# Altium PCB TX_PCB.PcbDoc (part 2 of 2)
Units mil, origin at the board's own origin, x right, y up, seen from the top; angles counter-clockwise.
Board outline 1955 x 2115 mil, 2 copper layers (Top Layer, Bottom Layer); 123 components, 95 nets, 485 pads, 266 vias.
Unrouted connection lines stored in the file: 109.

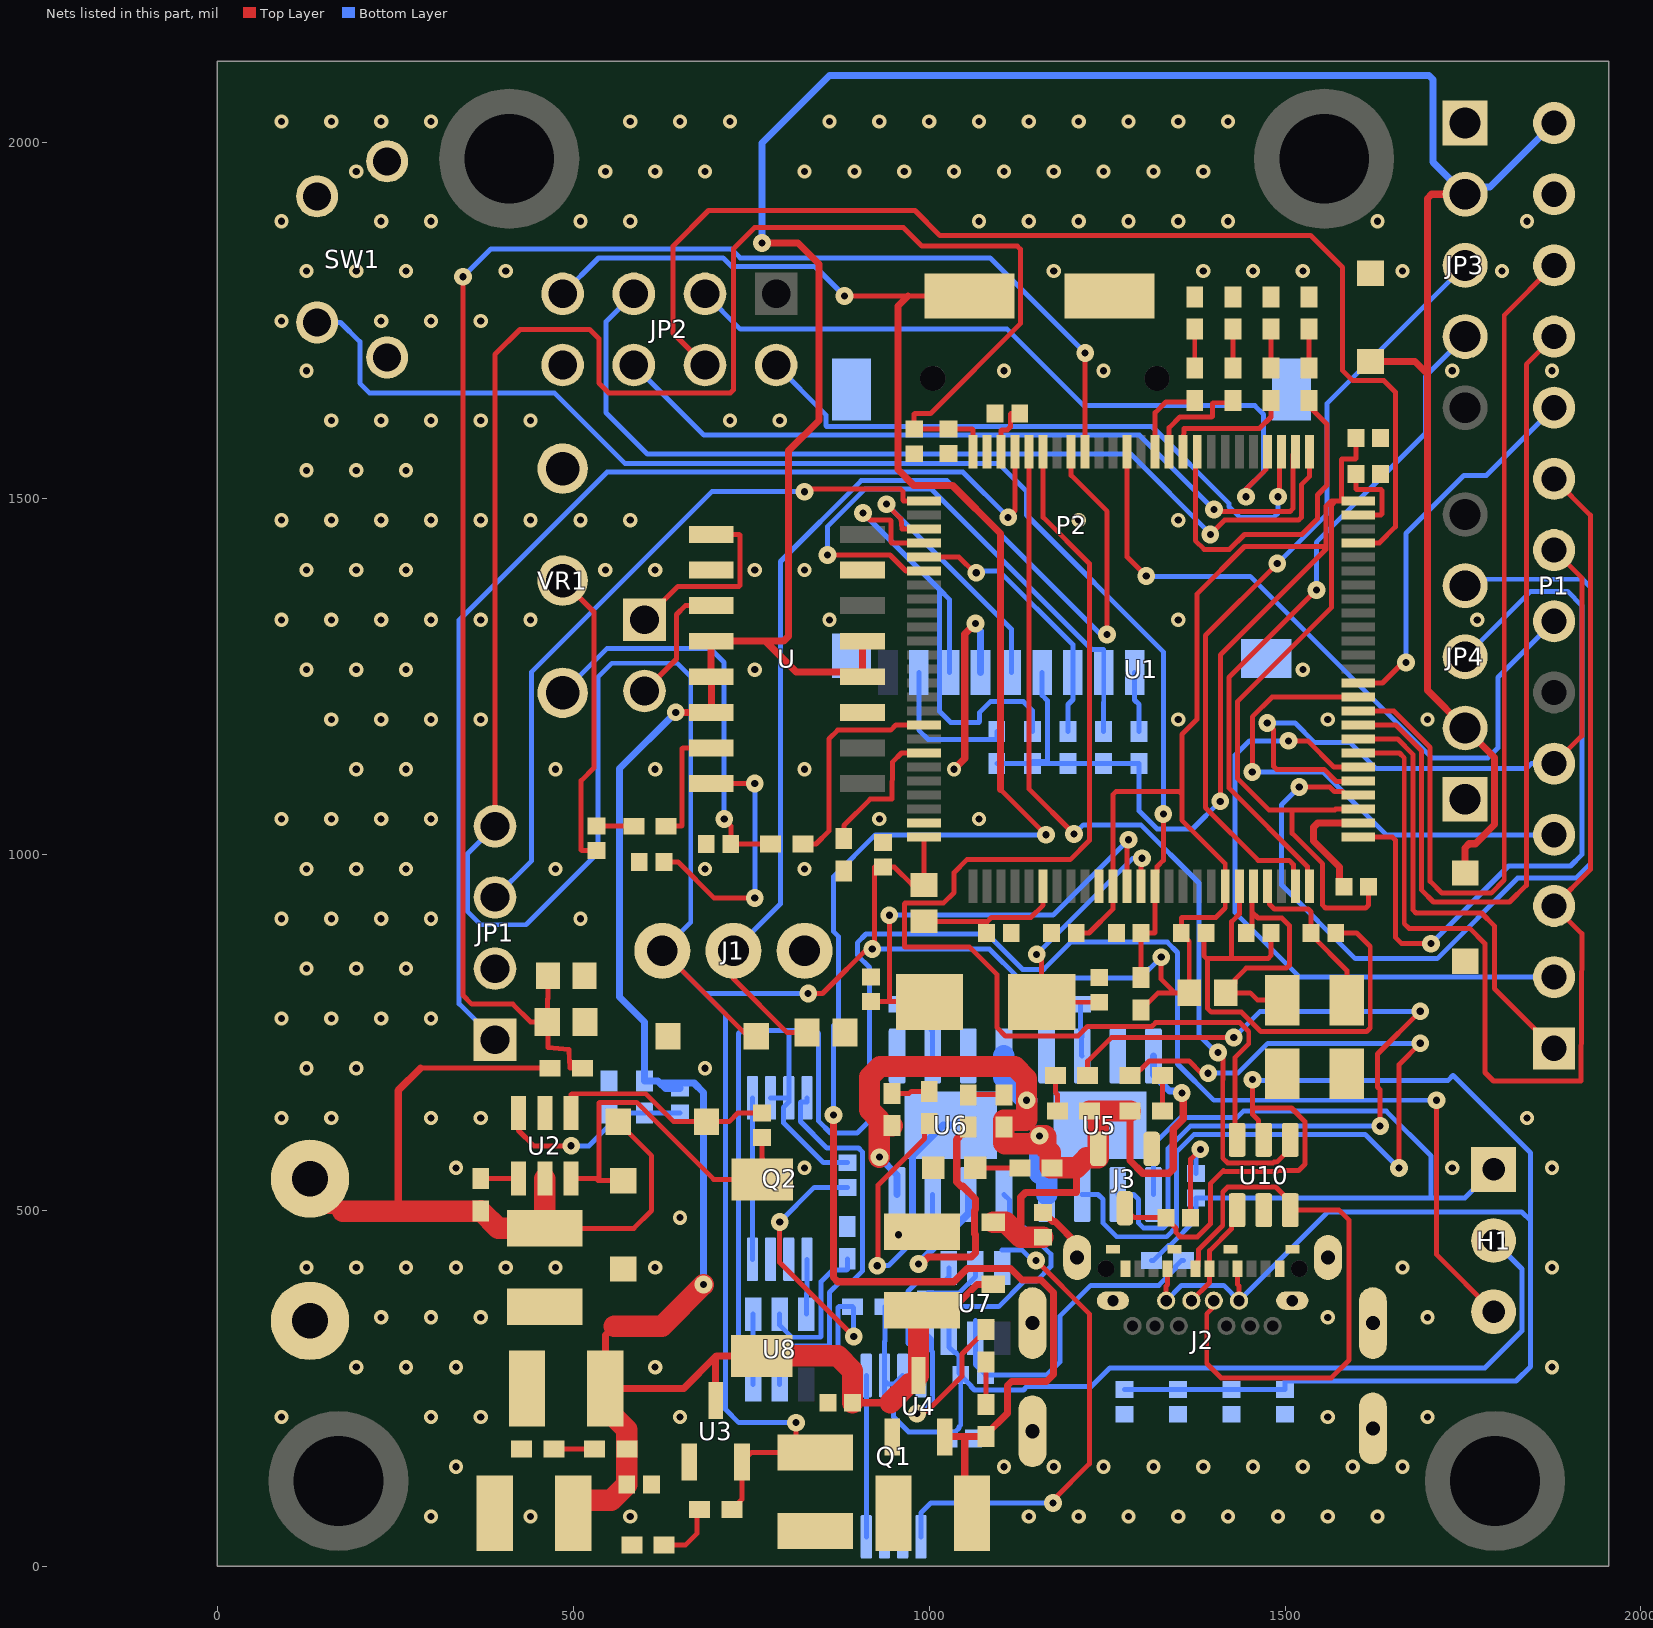
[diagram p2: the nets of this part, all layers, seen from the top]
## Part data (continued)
U: "Amplifier IC 2-Channel _Stereo_ Class D 16-SOP", Package="SOP-16 Diodes Inc."
U1: "ARMÂ® CortexÂ®-M4 STM32F4 Microcontroller IC 32-Bit Single-Core 168MHz 512KB (512K x 8) FLASH 100-LQFP (14x14)", Package="LQFP-100 STMicroelectronics"
U2: "Buck Switching Regulator IC Positive Adjustable 0.8V 1 Output 1A SOT-23-6 Thin, TSOT-23-6", Package="SOT-23 Texas Instruments"
U3 U4: "Linear Voltage Regulator IC 1 Output 250mA SOT-23-3", Package="SOT-23-3 Microchip"
U5 U6: "Complete single cell Li-Ion battery with a constant current / constant voltage linear charger", Package=Package
U7 U8: "One Cell Lithium-ion/Polymer Battery Protection IC", Package="SOT-23-6 Fortune Semiconductor"
U10: "17V Clamp 5A (8/20Âµs) Ipp Tvs Diode Surface Mount SOT-23-6", Package="SOT-23-6 STMicroelectronics"
Y1: library part NX5032GA-8.000M-STD-CSU-1, "CRYSTAL 8.0000MHZ 8PF SMD", ESR (Equivalent Series Resistance)="300 Ohms", Frequency Stability=±150ppm, Frequency Tolerance=±50ppm, Load Capacitance=8pF, Manufacturer="NDK America, Inc.", Operating Mode=Fundamental, Operating Temperature="-40°C ~ 150°C", Package / Case="2-SMD, No Lead", Ratings=AEC-Q200, Supplier Part Number 1=644-1132-1-ND

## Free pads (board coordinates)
  round 196.85 hole 125.98: 8(170,120) 8(410,1977.8) 8(1555,1977.8) 8(1795,120)

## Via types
v1: diameter 20, hole 10, Top Layer to Bottom Layer, 198 vias
v2: diameter 25, hole 10, Top Layer to Bottom Layer, 66 vias
v3: diameter 70.87, hole 59.06, Top Layer to Bottom Layer, 2 vias

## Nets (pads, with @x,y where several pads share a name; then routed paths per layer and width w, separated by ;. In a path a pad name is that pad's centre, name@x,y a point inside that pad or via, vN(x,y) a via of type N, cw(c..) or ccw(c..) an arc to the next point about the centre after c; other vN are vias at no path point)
+5: C19.2 C22.2 C23.2 C26.2 C31.2 C32.2 D6.2 D8.2 D9.2 JP3.2 JP4.2 L1.2 P1.14 R19.2 R21.2 U3.3 U4.3 U.4 U.5 U.6 U.12 U.13 | length 5966.3
  Top Layer w10: C22.2@545.12,249.92 C22.2@545.12,250 ; 557.62,337.5 545.12,325 C22.2@545.12,250 ; v2(644,1200) U.6@693.7,1200 694,1200 694,1250 U.5@693.7,1250 U.4@693.7,1300 770,1300 ; U3.3@700,232.92 700,294.9 ; L1.2@764.51,295.91 701,295.91 700,294.9 ; v2(765.05,1859.5) 815.5,1859.5 845,1830 845,1610 802.5,1567.5 802.5,1307 795.5,1300 770,1300 ; C32.2@892.32,229.92 945.35,229.92 ; U.13@906.3,1300 U.12@906.3,1250 899.49,1256.81 813.19,1256.81 770,1300 ; U4.3@980,256.92 985,261.92 U4.3@985,267.92 ; C31.2@990,349.8 1020.68,349.8 1067,396.12 D6.2@1090,396.12 ; D8.2@1620,1692.99 1682.5,1692.99 1700,1675.49 ; D9.2@1753,974.3 1753,1009.54 1758.86,1015.4 1767.54,1015.4 1794.5,1042.36 1794.5,1136.5 JP4.2@1753,1178 1700,1231 1700,1675.49 ; JP3.2@1753,1928 1705.86,1928 1700,1922.14 1700,1725 1700,1675.49 ; C22.2@545.12,250 655.09,250 700,294.9
  Top Layer w30: C23.2@500.12,74.92 500.12,82.35 510.71,92.94 553.14,92.94 C26.2@575.12,114.92 R21.2@575.12,164.92 575.12,192.36 545.12,222.36 C22.2@545.12,249.92 ; 557.62,337.5 624.5,337.5 v2(683,396) ; L1.2@764.51,295.91 871.42,295.91 892.32,275 C32.2@892.32,229.92 ; 945.35,229.92 972.35,256.92 U4.3@980,256.92 ; U4.3@985,267.92 985,349.8 C31.2@990,349.8
  Bottom Layer w10: v2(644,1200) 565,1121 565,800 600,765 R19.2@600,682.2 619,682.2 622.2,679 ; C19.2@650,671.88 629.31,671.88 622.2,679 ; v2(683,396) 683,666 670,679 650,679 622.2,679 ; v2(765.05,1859.5) 765.05,2000.05 860,2095 1702.14,2095 1708,2089.14 1708,1973 JP3.2@1753,1928 1763.14,1938.14 1788.14,1938.14 P1.14@1878,2028
+5_USB: C43.1 D6.1 D16.1 D17.1 D18.1 D19.1 J3.2 R36.2 U5.4 U5.8 U6.4 U6.8 | length 1613.2
  Top Layer w10: 1128.62,462.6 1128.62,518.62 1135.64,525.64 1207,525.64 1207,559.92 ; 1257.6,642.3 1259.98,639.92 ; D17.1@1282.36,639.92 1282.36,570.13 1300.05,552.44 1337.14,552.44 1343,558.3 1343,614.57 1357,628.57 1357,663 v2(1355,665)
  Top Layer w30: v2(930,575) 930,627.7 916.14,641.56 916.14,687.66 930.81,702.32 1120.1,702.32 1136.81,685.61 1136.81,655.19 v2(1137,655) 1137,628 1136,627 1105,627 D19.1@1105,617.28 1105,595 1106,594 v2@1157.5,594 ; 930,619.33 D18.1@947.95,619.33 ; D6.1@1090,483.72 1107.5,483.72 1128.62,462.6 C43.1@1160,462.6 ; v2(1155,605) 1163,605 1164,604 1164,587.5 1170,581.5 1170,559.92 R36.2@1172.64,559.92 1207,559.92 1221.08,574 1237.6,574 J3.2@1237.6,586.65 D16.1@1237.6,639.92 ; D16.1@1225.28,639.92 D16.1@1237.6,639.92 ; D17.1@1282.36,639.92 1259.98,639.92 D16.1@1237.6,639.92
  Bottom Layer w10: v2(930,575) 955,550 U6.8@955,522.48 ; U5.4@1315,717.36 1315,690.39 1337.52,667.87 1352.13,667.87 v2(1355,665)
  Bottom Layer w30: U6.4@1105,717.36 1105,687 v2(1137,655) ; v2(1155,605) 1155,552 1165,552 U5.8@1165,522.48
+5_USB_A: C34.1 C35.1 C36.1 C37.1 C42.2 J2.A4 J2.A9 J2.B4 J2.B9 J3.3 U10.5 | length 2590.6
  Top Layer w7: J3.3@1275,503.19 1288.27,489.92 C42.2@1332.68,489.92 1332.68,489.13 1347.01,474.8 1347.01,468.99 1353.1,462.9 1376.73,462.9 1394.97,481.14 1394.97,537.76 1413.2,556 1414.19,555.01 1488.4,555.01 1489.39,556 1518.9,556 1528,565.1 1528,625 1509,644 1461.92,644 1461.7,644.21 1454.29,644.21 ; J2.B9@1332.99,373.39 1332.99,394 1334.96,395.97 J2.A4@1334.96,418.27 ; J2.A9@1433.39,418.27 1433.39,395.97 1435.35,394 J2.B4@1435.35,373.39 ; v2(1454.29,683.89) 1454.29,644.21 ; U10.5@1470,599.33 1462.82,606.51 1462.82,626.73 1454.29,635.27 1454.29,644.21
  Bottom Layer w7: C35.1@1274.61,248.43 C34.1@1349.74,248.43 C36.1@1424.87,248.43 C37.1@1500,248.43 1500,260.5 1824.5,260.5 1845,281 1845,485.5 ; J2.B9@1332.99,373.39 1354.6,395 1413.74,395 J2.B4@1435.35,373.39 1559.97,498 1832.5,498 1845,485.5 ; v2(1454.29,683.89) 1455.18,683 1729.15,683 1736.04,689.89 1845,580.94 1845,485.5
+8.4: C21.2 D1.1 KF1.1 R7.2 R20.2 U2.5 | length 1156.7
  Top Layer w7: KF1.1@130,544.92 130,499 164.92,499 175.92,499 ; 285.08,700 R7.2@467.36,700 ; C21.2@460,475.04 585.04,475.04 610,500 610,576.93 562.99,623.94 D1.1@562.99,624.92
  Top Layer w10: 254,499 254,510 254,668.92 285.08,700
  Top Layer w30: 175.92,499 254,499 369.35,499 R20.2@370,499.65 ; R20.2@370.32,499.32 394.61,475.04 C21.2@460,475.04 U2.5@460,544.92
ADC_Pin: C29.2 R7.1 R15.2 U1.67 | length 2408
  Top Layer w7: v2(345,1812) 345,802.5 357.5,790 415,790 440,765 C29.2@463.43,765 ; R15.2@464.41,830 464.41,797.98 463.43,797 C29.2@463.43,765 ; R7.1@512.64,700 495,700 494,726 464.43,729 C29.2@463.43,765 ; U1.67@1219.15,1566 v2(1219.15,1704.85)
  Bottom Layer w7: v2(345,1812) 384,1851 722,1851 734.5,1838.5 1085.5,1838.5 v2(1219.15,1704.85)
ADC_VR_ESC: C24.2 J1.2 U1.68 | length 1621.5
  Top Layer w7: J1.2@725,865 725,825.5 800.5,750 C24.2@828.42,750 ; U1.68@1199.47,1566 1199.47,1533 1250,1482.47 v2(1250,1309.48)
  Bottom Layer w7: J1.2@725,865 791,931 791,1411.97 904.53,1525.5 1025.02,1525.5 1241.04,1309.48 v2(1250,1309.48)
Audio_PWM: R8.2 U1.92 | length 315.2
  Top Layer w7: R8.2@822.64,1015 841,1015 859,1033 859,1162.5 871.5,1175 946,1175 953.14,1182.14 U1.92@992.77,1182.14
B+: C38.1 H1.1 R27.2 U5.5 | length 1116.1
  Bottom Layer w7: R27.2@1312.36,430 1315.31,430 1336.52,451.2 1338.54,451.2 1375,487.66 C38.1@1375,517.6 1705,517.6 ; U5.5@1315,522.48 1315,592.64 1353.36,631 1432.64,631 1441.29,639.65 1642.35,639.65 1705,577 1705,517.6 ; H1.1@1793,557.92 1752.68,517.6 1705,517.6
B-: C41.2 H1.3 Q2.2 Q2.3 U8.6 | length 2725.1
  Top Layer w7: v2(1713,655) 1713,437.92 H1.3@1793,357.92
  Bottom Layer w7: U8.6@752.6,255.51 752.6,294.4 732,315 732,748.73 736.1,752.84 799.96,752.84 ; Q2.2@777.2,658.31 Q2.3@802.8,658.31 ; C41.2@885,567.25 851.48,567.25 795.39,623.34 795.39,645.13 802.8,652.54 Q2.3@802.8,658.31 ; v2(1713,655) 1400,655 1349,706 1349,862.7 1334.7,877 1199,877 1161,839 1131,839 1081.5,888.5 911.3,888.5 899,876.2 899,858.8 916.28,841.52 916.28,626.49 898.79,609 861.3,609 844.76,625.54 844.76,748.73 840.66,752.84 802.8,752.84 799.96,752.84 ; 799.96,752.84 802.8,750 Q2.3@802.8,658.31
B_COM: C39.2 C40.1 H1.2 Q1.2 Q1.3 R31.2 U6.5 U7.6 | length 1771.9
  Bottom Layer w7: 937.2,237.5 Q1.2@937.2,260.75 ; R31.2@937.64,364.92 937.64,316.43 937.2,316 Q1.2@937.2,260.75 ; Q1.3@962.8,268.31 950.87,256.38 ; C40.1@1027.68,180 C40.1@1027.68,180.79 ; U6.5@1105,522.48 1112.98,514.5 1112.98,480.75 1118.53,475.2 1134.5,475.2 1171,438.7 1171,421.3 1150.48,400.79 1133.33,400.79 1097.54,365 1037.61,365 1027.6,354.99 1027.6,308.39 1035.71,300.27 1037.44,300.27 1041.54,296.17 1041.54,271.81 C39.2@1044.36,269 ; H1.2@1793,457.92 1833,417.93 1833,331 1781,279 1254,279 1228,253 1137.51,253 1132.41,247.9 1063.67,247.9 1058.69,252.88 1058.69,253.88 1044.36,268.21 C39.2@1044.36,269 ; Q1.2@937.2,260.75 941.58,256.38 950.87,256.38 ; 950.87,256.38 950,255.51 950,210 970.9,189.1 1019.37,189.1 C40.1@1027.68,180.79 ; C40.1@1027.68,180.79 1035.99,189.1 1036.78,189.1 1042.01,194.33 1042.01,196.12 1044.36,198.46 C39.2@1044.36,269
BOOT0: R6.2 U1.94 | length 203
  Top Layer w7: R6.2@880,1022.64 880,1041 917,1078 947.65,1078 948.65,1130.42 961,1142.77 U1.94@992.77,1142.77
CHRG_LED: R28.1 U5.7 | length 1257.6
  Top Layer w7: R28.1@1282.36,689.92 1289.04,689.92 1304.37,705.25 1309.35,710.23 1365.23,710.23 1382.47,693 v2(1392,693) ; v2(1660,560) 1660,705 v2(1690,735)
  Bottom Layer w7: U5.7@1215,522.48 1237.31,522.48 1244.35,515.44 1244.35,482.25 1263.4,463.2 1333.57,463.2 1347.31,476.94 1347.31,582.01 1372.3,607 1612.46,607 1659.46,560 v2(1660,560) ; v2(1392,693) 1433.7,693 1475.7,735 v2(1690,735)
CHRG_LED_1: R32.1 U6.7 | length 371.5
  Top Layer w7: v2(927.1,422.5) 928.35,423.75 928.35,535.85 993.68,601.18 993.68,615.96 R32.1@1000,622.28
  Bottom Layer w7: v2(927.1,422.5) 942.96,422.5 1005,484.54 U6.7@1005,522.48
CLK_SD: P2.5 U1.78 | length 383.7
  Top Layer w7: v2(940,1492.5) 960.27,1472.23 961.54,1457.73 U1.78@992.77,1457.73
  Bottom Layer w7: v2(940,1492.5) 1115.35,1317.15 P2.5@1115.35,1255.88
CS_SD: P2.2 R18.1 U1.81 | length 803.2
  Top Layer w7: v2(857,1421) 945,1421 967.32,1398.68 U1.81@992.77,1398.68
  Bottom Layer w7: v2(857,1421) 857,1461 909.5,1513.5 1003.15,1513.5 1228.14,1288.51 1244.77,1288.51 1245.28,1288 P2.2@1245.28,1255.88 1245.28,1214.28 1245,1214 R18.1@1245,1173.36
DISPL_CS: P1.12 U1.35 | length 1321.3
  Top Layer w7: U1.35@1603.01,1201.83 1652.76,1201.83 1704,1150.58 1704,962.57 1720.57,946 1789.5,946 1808,964.5 1808,1758 P1.12@1878,1828
DISPL_DC: P1.10 U1.37 | length 541.6
  Top Layer w7: U1.37@1603.01,1241.2 1637,1241.2 1665.8,1270 v2(1670,1270)
  Bottom Layer w7: v2(1670,1270) 1670,1451.56 1751.44,1533 1783,1533 P1.10@1878,1628
DISPL_LED: P1.7 U1.64 | length 1002
  Top Layer w7: U1.64@1278.21,1566 1278.21,1418.29 v2(1305,1391.5)
  Bottom Layer w7: v2(1305,1391.5) 1305.5,1391 1451,1391 1706,1136 1785,1136 1799,1150 1799,1249 P1.7@1878,1328
DISPL_MOSI: P1.3 P1.9 U1.32 | length 1650.8
  Top Layer w7: U1.32@1603.01,1142.77 1660.9,1142.77 1667.5,1136.17 1667.5,903.11 1674.1,896.51 1759.49,896.51 1781,875 1781,694 1793,682 1916,682 1917,889 P1.3@1878,928 1929,979 1929,1477 P1.9@1878,1528
DISPL_RST: P1.11 U1.34 | length 1250.4
  Top Layer w7: U1.34@1603.01,1182.14 1655.47,1182.14 1692,1145.61 1692,950.1 1708.64,933.46 1815.46,933.46 1839,957 1839,1689 P1.11@1878,1728
DISPL_SCK: P1.5 P1.8 U1.30 | length 957.5
  Top Layer w7: v2(1475,1185) 1484,1176 1484,1124.1 1488.1,1120 1555,1120 1572.16,1102.84 1602.45,1102.84 U1.30@1603.01,1103.4 ; P1.5@1878,1128 1917,1167 1917,1389 P1.8@1878,1428
  Bottom Layer w7: v2(1475,1185) 1514.2,1185 1541.8,1157.4 1591.6,1157.4 1628.17,1120.83 1838.83,1120.83 1846,1128 P1.5@1878,1128
GND: C1.1 C2.1 C3.1 C4.1 C5.1 C6.1 C7.2 C8.1 C9.1 C10.1 C11.1 C12.1 C13.1 C14.1 C15.1 C17.1 C18.1 C21.1 C22.1 C23.1 C24.1 C25.2 C26.1 C27.2 C28.1 C29.1 C30.2 C31.1 C32.1 C33.1 C34.2 C35.2 C36.2 C37.2 C38.2 C40.2 C42.1 C43.2 D2.1 D3.2 D4.1 D5.2 D8.1 D9.1 D10.2 D11.2 D12.2 D13.2 D14.2 D15.2 J1.1 J2.A1 J2.A12 J2.B1 J2.B12 J2.S J3.1 JP1.2 JP2.5 JP3.1 JP4.1 KF1.2 P1.13 P2.6 P2.G1 P2.G2 P2.G3 P2.G4 Q1.6 Q1.7 Q2.6 Q2.7 R6.1 R10.1 R15.1 R22.1 R25.1 R26.2 R30.2 SW1.1 SW1.G1 SW1.G2 U1.10 U1.20 U1.27 U1.74 U1.99 U2.2 U3.1 U4.1 U5.1 U5.3 U5.9 U6.1 U6.3 U6.9 U10.2 U.2 U.11 U.15 VR1.2 | length 1920.6
  Top Layer w7: v2(983,215) 986.44,218.44 997.44,218.44 1046,267 1046,298.56 1068.74,321.3 1071.69,321.3 1080,329.61 D15.2@1080,332.56 ; C42.1@1367.32,489.92 1367.32,572.32 v2(1381,586) ; C12.1@1388.92,890 1386,887.07 1386,858.1 1390.1,854 ; U1.20@1435.69,955.76 1435.69,916.64 1425,905.95 1425,854 ; C6.1@1480.12,890 1480.12,858.12 1476,854 1425,854 ; C7.2@1571.32,890 1600.68,890 1619.71,870.97 1619.71,756.62 1614.73,751.64 1466.03,751.64 1438.87,778.8 1396.34,778.8 1391.36,783.78 1391.36,852.74 1390.1,854 ; 1390.1,854 1425,854
  Top Layer w10: v1(1035,1120) 1050,1135 1050,1310 v2(1065,1325) ; C43.2@1160,497.25 1160.79,497.25 1173.62,484.41 1176.74,484.41 1207.99,453.16 J2.S@1207.99,434.02 ; C11.1@1582.68,955 1576.49,961.18 1576.49,982.6 1540,1019.09 1540,1038.49 1545.86,1044.35 U1.27@1603.01,1044.35
  Bottom Layer w7: v2(983,215) 984.53,215 1004.76,235.23 1004.76,301.38 1003.31,302.83 1003.31,319.05 R26.2@995,327.36 ; C38.2@1375,552.24 1375,580 v2(1381,586)
  Bottom Layer w10: v2(956.76,466) 961.52,466 976.81,481.29 976.81,577.42 1019.31,619.92 U6.9@1030,619.92 ; R26.2@994,326 995,327 R26.2@995,327.36 ; v2(1065,1325) 1065,1320.94 1072.05,1313.89 P2.6@1072.05,1255.88
  other v1: 300,70 440,70 580,70 1140,70 1210,70 1280,70 1350,70 1420,70 1490,70 1560,70 1630,70 335,140 1105,140 1175,140 1245,140 1315,140 1385,140 1455,140 1525,140 1595,140 1665,140 90,210 300,210 370,210 650,210 1560,210 1700,210 195,280 265,280 335,280 615,280 1875,280 230,350 300,350 370,350 1560,350 1700,350 125,420 195,420 265,420 335,420 405,420 475,420 615,420 1665,420 1875,420 650,490 335,560 825,560 1735,560 1875,560 90,630 160,630 300,630 370,630 1840,630 125,700 195,700 685,700 90,770 160,770 230,770 300,770 125,840 195,840 265,840 90,910 160,910 230,910 300,910 510,910 125,980 195,980 265,980 475,980 685,980 825,980 90,1050 160,1050 230,1050 300,1050 930,1050 1070,1050 195,1120 265,1120 475,1120 615,1120 825,1120 160,1190 230,1190 300,1190 370,1190 1350,1190 1560,1190 1700,1190 125,1260 195,1260 265,1260 755,1260 1525,1260 90,1330 160,1330 230,1330 300,1330 370,1330 440,1330 860,1330 1350,1330 1770,1330 125,1400 195,1400 265,1400 545,1400 615,1400 755,1400 825,1400 90,1470 160,1470 230,1470 300,1470 370,1470 440,1470 510,1470 580,1470 1210,1470 1350,1470 125,1540 195,1540 265,1540 160,1610 230,1610 300,1610 370,1610 440,1610 720,1610 790,1610 125,1680 1105,1680 1245,1680 1735,1680 1875,1680 90,1750 230,1750 300,1750 370,1750 125,1820 195,1820 265,1820 405,1820 1175,1820 1385,1820 1455,1820 1525,1820 1665,1820 1805,1820 90,1890 230,1890 300,1890 510,1890 580,1890 1070,1890 1140,1890 1210,1890 1280,1890 1350,1890 1420,1890 1630,1890 1840,1890 195,1960 545,1960 615,1960 685,1960 825,1960 895,1960 965,1960 1035,1960 1105,1960 1175,1960 1245,1960 1315,1960 1385,1960 90,2030 160,2030 230,2030 300,2030 580,2030 650,2030 720,2030 860,2030 930,2030 1000,2030 1070,2030 1140,2030 1210,2030 1280,2030 1350,2030 1420,2030
JOY1_X: JP3.3 U1.24 | length 1101.3
  Top Layer w7: v2(1489,1409) 1388,1308 1388,1066.3 1462.3,992 1505.88,992 1511.63,986.25 1511.63,958.56 U1.24@1514.43,955.76
  Bottom Layer w7: v2(1489,1409) 1559.23,1479.23 1559.23,1634.23 JP3.3@1753,1828
JOY1_Y: JP3.4 U1.25 | length 956.6
  Top Layer w7: U1.25@1534.11,955.76 1531.31,958.56 1531.31,983.53 1421,1093.85 1421,1249 v2(1544,1372)
  Bottom Layer w7: v2(1544,1372) 1544,1438.87 1697,1591.87 1697,1672 JP3.4@1753,1728
JOY2_X: JP4.3 U1.26 | length 1068.2
  Top Layer w7: U1.26@1603.01,1024.66 1650.9,1024.66 1655,1020.56 1655,883.87 1663.87,875 v2(1705,875)
  Bottom Layer w7: v2(1705,875) 1814,984 1901,984 1917,1000 1917,1350 1897,1370 1845,1370 JP4.3@1753,1278
JOY2_Y: JP4.4 U1.29 | length 1345.7
  Top Layer w7: v2(1520,1095) 1563.03,1095 1569.43,1088.6 1580.8,1088.6 1585.69,1083.72 U1.29@1603.01,1083.72
  Bottom Layer w7: v2(1520,1095) 1495,1070 1495,957.68 1598.68,854 1713.7,854 1826.7,967 1908.5,967 1929,987.5 1929,1376 1918,1387 1753,1387 JP4.4@1753,1378
LED1: R1.1 U1.59 | length 502.7
  Top Layer w7: U1.59@1376.63,1566 1374,1563.37 1374,1441.3 1386.3,1429 1422.03,1429 1443.03,1450 1523.64,1450 1545.5,1471.86 1545.5,1505.5 1559,1519 1559,1604.72 1533.72,1630 R1.1@1533.72,1638.36
LED2: R2.1 U1.60 | length 185.3
  Top Layer w7: U1.60@1356.95,1566 1357.95,1599 1464.19,1599 1480.19,1615 R2.1@1480.19,1638.36
LED3: R3.1 U1.61 | length 151.8
  Top Layer w7: U1.61@1337.26,1566 1337.26,1600 1352.26,1615 1397,1615 1398,1616 1398,1634 1399,1635 1426.67,1635 R3.1@1426.67,1638.36
LED4: R5.1 U1.62 | length 119.2
  Top Layer w7: U1.62@1317.58,1566 1317.58,1621.08 1332.5,1636 1373.14,1636 R5.1@1373.14,1638.36
MISO_SD: P2.7 R12.1 U1.79 | length 757.5
  Top Layer w7: v2(907,1480) 916.69,1470.31 945,1470.31 946.3,1469.01 946.3,1439 947.25,1438.05 U1.79@992.77,1438.05
  Bottom Layer w7: v2(907,1480) 1014.41,1372.59 ; P2.7@1028.74,1255.88 1028.74,1358.26 1014.41,1372.59 ; R12.1@1145,1173.36 1145,1202.5 1132.5,1215 1086,1215 1071,1200 1071,1186.88 1070,1185.88 1030,1185.88 1014.41,1201.47 1014.41,1255.88 1014.41,1372.59
MOSI_SD: P2.3 R11.1 U1.80 | length 386.8
  Top Layer w7: U1.80@992.77,1418.36 1041.64,1418.36 1063.9,1396.1 v2(1066.1,1396.1)
  Bottom Layer w7: v2(1066.1,1396.1) 1068.44,1398.44 1098.52,1398.44 1201.97,1295 P2.3@1201.97,1255.88 1201.97,1217.97 1195,1211 R11.1@1195,1173.36
NetC16_1: C16.1 VR1.0 | length 426.1
  Top Layer w7: VR1.0@485,1385 529,1341 529,1122 511,1104 511,1006.68 512,1005.68 C16.1@532.64,1005.68
NetC16_2: C16.2 R9.1 | length 52.5
  Top Layer w7: C16.2@532.64,1040.32 558,1040.32 558.32,1040 R9.1@585,1040
NetC17_2: C17.2 R8.1 VR1.1 | length 576.1
  Top Layer w7: v2(712,1050) 721.32,1040.68 C17.2@721.32,1015 R8.1@777.36,1015
  Bottom Layer w7: VR1.1@485,1227.52 547.48,1290 692,1290 712,1270 v2(712,1050)
NetC18_2: C18.2 U.8 | length 371.1
  Top Layer w7: C18.2@627.32,990 647,990 698,939 v2(755,939) ; U.8@693.7,1100 v2(755,1100)
  Bottom Layer w7: v2(755,939) v2(755,1100)
NetC19_1: C19.1 R19.1 R22.2 U2.3 | length 314
  Top Layer w7: U2.3@423,636.92 423,612.5 444.5,591 v2(497,591)
  Bottom Layer w7: v2(497,591) 522,591 550,619 R22.2@550,636.92 ; C19.1@650,637.24 624.31,637.24 624,636.92 R19.1@600,636.92 574,636.92 ; R22.2@550,636.92 574,636.92 ; R22.2@550,636.92 574,636.92
NetC20_1: C20.1 D2.2 L1.1 U2.6 | length 517.4
  Top Layer w7: U2.6@497,544.92 532,544.92 534.99,541.93 537,541.93 ; D2.2@570,541.93 537,541.93 ; C20.1@765,602.6 765,573.49 765.49,573 L1.1@765.49,543.94 697.19,543.94 589,652.12 537,652.12 536,651.12 536,542.93 537,541.93
NetC20_2: C20.2 D1.2 U2.1 | length 316
  Top Layer w7: U2.1@497,636.92 497,663.12 498,664.12 601.8,664.12 641,624.92 D1.2@687.01,624.92 719,624.92 731.32,637.24 C20.2@765,637.24
NetC39_1: C39.1 R27.1 U7.5 | length 467.1
  Bottom Layer w7: 1065,345.51 U7.5@1065,320.59 1065,283.79 1079,269.79 C39.1@1079,269 1165.5,269 1184,287.5 1184,352 1227,395 1322.64,395 1346.37,418.74 1346.37,421.69 1354.69,430 R27.1@1357.64,430
NetC41_1: C41.1 R31.1 U8.5 | length 562.2
  Top Layer w7: v2(790,484) 790,427 v2(894,323)
  Bottom Layer w7: U8.5@790,255.51 790,279.5 807.5,297 871,297 872,298 872,363.92 873,364.92 R31.1@892.36,364.92 894,363.28 v2(894,323) ; v2(790,484) 838.6,532.6 C41.1@885,532.6
NetD3_1: D3.1 R21.1 | length 57.2
  Top Layer w7: D3.1@472.64,164.92 R21.1@529.84,164.92
NetD5_1: D5.1 R36.1 | length 62.8
  Top Layer w7: D5.1@1064.53,559.92 R36.1@1127.36,559.92
NetD10_1: D10.1 R1.2 | length 54.7
  Top Layer w7: R1.2@1533.72,1683.64 D10.1@1533.72,1738.36
NetD11_1: D11.1 R2.2 | length 54.7
  Top Layer w7: R2.2@1480.19,1683.64 D11.1@1480.19,1738.36
NetD12_1: D12.1 R3.2 | length 54.7
  Top Layer w7: R3.2@1426.67,1683.64 D12.1@1426.67,1738.36
NetD13_1: D13.1 R5.2 | length 54.7
  Top Layer w7: R5.2@1373.14,1683.64 D13.1@1373.14,1738.36
NetD14_1: D14.1 R23.1 | length 90.1
  Top Layer w7: D14.1@627.64,29.92 657.5,29.92 674,46.42 674,79.92 R23.1@677.36,79.92
NetD15_1: D15.1 R24.1 | length 59.7
  Top Layer w7: R24.1@1080,227.56 D15.1@1080,287.28
NetD16_2: D16.2 R29.1 | length 51.1
  Top Layer w7: R29.1@1177.36,689.92 1177.36,665.64 1180,663 D16.2@1180,639.92
NetD17_2: D17.2 R28.2 | length 50
  Top Layer w7: D17.2@1327.64,639.92 R28.2@1327.64,689.92
NetD18_2: D18.2 R32.2 | length 53.3
  Top Layer w7: D18.2@947.95,664.61 972,664.61 974.95,667.56 R32.2@1000,667.56
NetD19_2: D19.2 R33.1 | length 50.9
  Top Layer w7: R33.1@1055,662.56 1055,663 1105,663 D19.2@1105,662.56
NetJ2_A6: J2.A6 J2.B6 U10.3 | length 838.1
  Top Layer w7: J2.A6@1374.33,418.27 1377.72,421.66 1377.72,429.78 1378.63,430.68 1378.63,445.26 1412.48,479.11 1412.48,499.51 1412.48,526.15 1419.16,532.83 1425.2,532.83 1487.29,532.83 1507.4,512.72 U10.3@1507.4,500.51 ; J2.B6@1399.92,373.39 1396.36,369.83 1396.36,361.36 1390,355 1390,285 1410,265 1565,265 1590,290 1590,486.5 1575.5,501 U10.3@1507.4,501
NetJ2_A7: J2.A7 J2.B7 U10.1 | length 153.7
  Top Layer w7: J2.B7@1368.42,373.39 1394.02,398.98 J2.A7@1394.02,418.27 1394.02,443.68 1424.48,474.14 1424.48,492.4 U10.1@1432.6,500.51
NetJP5_1: JP5.1 U.1 | length 265.6
  Top Layer w7: JP5.1@600,1330 647,1377 733,1377 734,1378 734,1449 733,1450 U.1@693.7,1450
NetJP5_2: JP5.2 U.3 | length 180
  Top Layer w7: JP5.2@600,1230 645,1275 645,1337.5 657.5,1350 U.3@693.7,1350
NetP2_1: P2.1 R17.1 | length 85.2
  Bottom Layer w7: P2.1@1288.58,1255.88 1288.58,1217.42 1295,1211 R17.1@1295,1173.36
NetP2_8: P2.8 R13.1 | length 207.2
  Bottom Layer w7: P2.8@985.43,1255.88 985.43,1175 998.43,1162 1095,1162 R13.1@1095,1173.36
NetQ1_1: Q1.1 Q1.8 | length 226.8
  Bottom Layer w7: Q1.8@911.61,41.54 Q1.1@911.61,268.31
NetQ1_4: Q1.4 U7.1 | length 204.2
  Bottom Layer w7: Q1.4@988.39,268.31 984.01,272.68 984.01,300 979.91,304.1 979.67,304.1 974.69,309.08 974.69,309.32 970,314.01 970,386.23 982.86,399.09 1019.48,399.09 1027.6,407.21 U7.1@1027.6,419.41
NetQ1_5: Q1.5 U7.3 | length 670.3
  Top Layer w7: v2(1150,430) 1225,355 1225,144.16 1174,93.16 v2(1174,89)
  Bottom Layer w7: Q1.5@988.39,41.54 988.39,75 1002.39,89 v2(1174,89) ; 1102.4,444.33 1130.67,444.33 1145,430 v2@1148.67,430
NetQ2_1: Q2.1 Q2.8 | length 226.8
  Bottom Layer w7: Q2.8@751.61,431.54 Q2.1@751.61,658.31
NetQ2_4: Q2.4 U8.1 | length 592
  Bottom Layer w7: U8.1@752.6,354.33 752.6,322 764.6,310 859,310 860,311 860,385 875,400 891.31,400 906.1,414.79 906.1,498.68 906.1,582.58 900.68,588 856.31,588 819.17,625.14 819.17,651.94 819.69,652.46 828.39,652.46 Q2.4@828.39,658.31
NetQ2_5: Q2.5 U8.3 | length 77.6
  Bottom Layer w7: U8.3@827.4,354.33 827.4,383.4 828.39,384.38 Q2.5@828.39,431.54
NetR9_2: R9.2 U.7 | length 172.3
  Top Layer w7: R9.2@630.28,1040 652,1040 653,1041 653,1149 654,1150 U.7@693.7,1150
NetR10_2: R10.2 U6.2 | length 73.5
  Bottom Layer w7: R10.2@1002.64,789.92 1002.64,754.36 1005,752 U6.2@1005,717.36
NetR20_1: R20.1 U2.4 | length 53
  Top Layer w7: R20.1@370,544.92 U2.4@423,544.92
NetR25_2: R25.2 U5.2 | length 74.1
  Bottom Layer w7: R25.2@1212.64,789.92 1212.64,754.36 1215,752 1215,743.51 1214.31,742.81 1214.31,718.06 U5.2@1215,717.36
NetR26_1: R26.1 U7.2 | length 100.3
  Bottom Layer w7: R26.1@990,375.59 998.31,383.9 1041.7,383.9 1065,407.21 U7.2@1065,419.41
NetR30_1: R30.1 U8.2 | length 216.8
  Bottom Layer w7: U8.2@790,354.33 790,339 807,322 847,322 848,323 848,400 864.5,416.5 884,416.5 885,417.5 R30.1@885,432.28
NRST: C3.2 R4.1 SW1.2 U1.14 | length 1916.1
  Top Layer w7: R4.1@1297.72,827.32 C3.2@1297.72,890 1316.58,890 1317.58,891 1317.58,973.09 1320.38,975.89 1320.38,983.53 1329,992.15 v2(1329,1057)
  Bottom Layer w7: SW1.2@140,1747.83 173,1747.83 200,1720.83 200,1662.5 213.5,1649 473.31,1649 572.81,1549.5 1097.91,1549.5 1136.7,1510.7 1136.7,1477.3 1329,1285 v2(1329,1057)
OSC_IN: C5.2 U1.12 Y1.2 | length 650.6
  Top Layer w7: C5.2@918,793.68 943,793.68 ; v2(944,915) 944,794.68 943,793.68 ; Y1.2@1000.52,793 958.68,793 958,793.68 943,793.68 ; U1.12@1278.21,955.76 1278.21,974 1278,974.21 1278,1015.89 1280,1017.89 v2(1280,1021)
  Bottom Layer w7: v2(944,915) 1174,915 v2(1280,1021)
OSC_OUT: C4.2 U1.13 Y1.1 | length 394.6
  Top Layer w7: v2(1151,860) 1158,853 Y1.1@1158,793 1198,793 1198.32,792.68 C4.2@1239,792.68 ; U1.13@1297.89,955.76 1297.89,993.89 v2(1299,995)
  Bottom Layer w7: v2(1151,860) 1286,995 v2(1299,995)
RF_CE: JP2.6 U1.52 | length 1094.3
  Top Layer w7: v2(1400,1485) 1403,1482 1506.9,1482 1511,1486.1 1511,1562.57 U1.52@1514.43,1566
  Bottom Layer w7: JP2.6@585,1688 683.29,1589.71 1295.29,1589.71 v2(1400,1485)
RF_CSN: JP2.3 U1.51 | length 1338.2
  Top Layer w7: v2(1395,1450) 1415,1470 1518.9,1470 1523,1474.1 1523,1520 1534.11,1531.11 U1.51@1534.11,1566
  Bottom Layer w7: JP2.3@585,1788 546,1749 546,1621 604,1563 1283.16,1563 1395,1451.16 v2(1395,1450)
RF_MISO: JP2.8 U1.53 | length 895.6
  Top Layer w7: v2(1490,1503) 1492.37,1505.37 1492.37,1563.63 U1.53@1494.74,1566
  Bottom Layer w7: JP2.8@785,1688 854.88,1618.12 854.88,1602.82 856,1601.71 1312.99,1601.71 1421,1493.7 1421,1489.3 1436.3,1474 1484,1474 1490,1480 v2(1490,1503)
RF_MOSI: JP2.2 U1.54 | length 1057.7
  Top Layer w7: v2(1445,1503) 1445,1513 1473,1541 1473,1566 U1.54@1475.06,1566
  Bottom Layer w7: JP2.2@685,1788 734.58,1738.42 1109.58,1738.42 1217,1631 1457.5,1631 1470,1618.5 1470,1538 1445,1513 v2(1445,1503)
RF_SCK: JP2.7 U1.47 | length 1662.7
  Top Layer w7: JP2.7@685,1688 640,1733 640,1855 690,1905 980,1905 1015,1870 1536,1870 1581,1825 1581,1680 1595,1666 1639,1666 1655,1650 1655,1460.55 1632.5,1438.05 U1.47@1603.01,1438.05
STDBY_LED: R29.2 U5.6 | length 1233
  Top Layer w7: R29.2@1222.64,689.92 1222.64,709.83 1255.81,743 v2(1428,743) ; v2(1633.65,618.65) 1633.65,669.94 1630,673.58 1630,720 v2(1690,780)
  Bottom Layer w7: U5.6@1265,522.48 1287.31,522.48 1294.35,515.44 1294.35,482.25 1301.4,475.2 1328.6,475.2 1335.31,481.91 1335.31,586.98 1367.33,619 1633.3,619 v2(1633.65,618.65) ; v2(1428,743) 1465,780 v2(1690,780)
STDBY_LED_1: R33.2 U6.6 | length 411.7
  Top Layer w10: v2(985,425) 989.06,425 998.59,434.53 1059.14,434.53 1065,440.39 1065,465.94 1063.66,467.28 1063.66,500.17 1065,501.51 1065,516.47 1047.29,534.17 1044.64,534.17 1038.78,540.03 1038.78,600.09 1046.21,607.52 1048.19,607.52 1055,614.33 R33.2@1055,617.28
  Bottom Layer w10: v2(985,425) 985,426.39 1018.26,459.65 1019.13,459.65 1055,495.51 U6.6@1055,522.48
SWCLK: JP1.3 U1.76 | length 1009.9
  Top Layer w7: v2(825,1510) 828.5,1513.5 960,1513.5 963,1510.5 963,1498.1 964,1497.1 U1.76@992.77,1497.1
  Bottom Layer w7: JP1.3@390,940 441,991 441,1256.5 694.5,1510 v2(825,1510)
SWDIO: JP1.1 U1.72 | length 1590.4
  Top Layer w7: v2(1111,1473.99) 1120.73,1483.71 U1.72@1120.73,1566
  Bottom Layer w7: JP1.1@390,740 339.58,790.42 339.58,1329.64 547.43,1537.5 1047.49,1537.5 v2(1111,1473.99)
TOUCH_CS: P1.4 U1.36 | length 698.7
  Top Layer w7: v2(1454,1116) 1454,1193.7 1481.81,1221.51 U1.36@1603.01,1221.51
  Bottom Layer w7: v2(1454,1116) 1554,1116 1642,1028 P1.4@1878,1028
TOUCH_INT: P1.1 U1.33 | length 634.5
  Top Layer w7: U1.33@1603.01,1162.46 1658.19,1162.46 1680,1140.64 1680,922.1 1684.1,918 1776,918 1794,900 1794,812 P1.1@1878,728
TOUCH_MISO: P1.2 U1.31 | length 903.6
  Top Layer w7: v2(1505,1160) 1531.97,1160 1568.88,1123.09 U1.31@1603.01,1123.09
  Bottom Layer w7: v2(1505,1160) 1449.99,1160 1430,1140.01 1430,918.5 1520.5,828 P1.2@1878,828
USB_DM: U1.70 U10.6 | length 1700.2
  Top Layer w7: U1.70@1160.1,1566 1160.1,1474 1225,1409.1 1225,1020 1198,993 1053,993 1035,975 1035,947 1020,932 966,932 965,931 965,871 966,870 1057,870 1095,832 1095,757.37 1107.24,745.13 1208.76,745.13 1222.42,758.78 1313.05,758.78 1318.27,764 1436.7,764 1449,751.7 1449,734.3 1430,715.3 1430,601.93 U10.6@1432.6,599.33
USB_DP: U1.71 U10.4 | length 1316.5
  Top Layer w7: U1.71@1140.41,1566 1140.41,1092.09 v2(1203.5,1029) ; v2(1406,722) 1413,715 1413,684.3 1412.48,683.79 1412.48,573.69 1419.16,567.01 1483.43,567.01 1484.42,568 1488.28,568 1507.4,587.13 U10.4@1507.4,599.33
  Bottom Layer w7: v2(1203.5,1029) 1216.5,1042 1297.33,1042 1379,960.33 1379,746.3 1411,714.3 1406,719.3 v2(1406,722)
VBAT: C15.2 R16.2 U1.6 | length 219.6
  Top Layer w7: R16.2@992.77,906.41 1079.27,906.41 1080.68,905 ; C15.2@1080.68,890 1080.68,905 ; U1.6@1160.1,955.76 1160.1,929 1143.1,912 1087.68,912 1080.68,905
VCAP_1: C1.2 U1.49 | length 124.8
  Top Layer w7: C1.2@1599.68,1534.69 1599.68,1514 1600.68,1513 1635,1513 1636,1512 1636,1478.42 1635,1477.42 U1.49@1603.01,1477.42
VCAP_2: C2.2 U1.73 | length 76.8
  Top Layer w7: U1.73@1101.04,1566 1101.04,1596 1102.04,1597 1110,1597 1114,1601 1114,1619 1115,1620 C2.2@1127.32,1620
VCCNRF: C25.1 C33.2 JP2.4 R24.2 U4.2 | length 3160.6
  Top Layer w7: v2(881,1785) 970,1785 C25.1@1056.57,1785 ; R24.2@1080,182.28 R24.2@1080,185.24 ; 1100,1092 v2(1164,1028)
  Top Layer w10: v2(865.76,634.24) 865.76,405.86 871.62,400 1035,400 1053.43,418.43 1114.14,418.43 1130.28,402.29 1157.3,402.29 1174.69,384.9 1174.69,269.69 1165,260 1115.86,260 1110,254.14 1110,215.24 R24.2@1080,185.24 ; 970,1785 956,1771 956,1541 978,1519 1032.5,1519 1100,1451.5 1100,1092 ; U4.2@1022,181.92 1022.36,182.28 1050,182.28 ; C33.2@1060.12,74.92 1050,85.04 1050,182.28 ; R24.2@1080,182.28 1050,182.28
  Bottom Layer w7: JP2.4@485,1788 535.42,1838.42 710.58,1838.42 722.5,1826.5 839.5,1826.5 v2(881,1785) ; v2(865.76,634.24) 865.76,760.14 872.87,767.25 872.87,884.83 865.76,891.94 865.76,969.39 924.37,1028 v2(1164,1028)
VDD1: C8.2 C9.2 C10.2 C11.2 C12.2 C13.2 C14.2 C28.2 D4.2 J1.3 JP1.4 P2.4 R4.2 R11.2 R12.2 R13.2 R14.1 R16.1 R17.2 R18.2 R23.2 U1.11 U1.19 U1.28 U1.50 U1.75 U1.100 U3.2 | length 8872.5
  Top Layer w7: JP1.4@390,1040 390,1703 425,1738 523,1738 536,1725 536,1662.5 549.5,1649 720.9,1649 725,1653.1 725,1851.5 754.5,1881 964,1881 990,1855 1123.97,1855 1128.07,1850.9 1128.07,1746 1002.07,1620 980,1620 979,1619 C14.2@979,1598 1002,1598 1002.32,1598.32 C13.2@1027,1598.32 1060.35,1598.32 1061.67,1597 U1.75@1061.67,1566 ; J1.3@625,865 745,745 D4.2@757.01,745 ; R23.2@722.64,79.92 737,94.28 U3.2@737,146.92 750.12,160.04 C28.2@813,160.04 ; v2(813,202) C28.2@813,160.04 ; v2(830,805) 850,805 v2@920,875 ; C28.2@840,160.04 C28.2@813,160.04 ; v2(920,867.5) v2@920,875 ; U1.100@992.77,1024.66 R16.1@992.77,957.59 976.09,957.59 951,982.68 C10.2@935,982.68 923,982.68 923,878 v2@920,875 ; C9.2@1206.52,890 1224.52,890 1258.52,924 U1.11@1258.52,955.76 1258.52,1084.9 1262.62,1089 1350.9,1089 1355,1084.9 ; R4.2@1297.72,782.05 1321.68,806 1345,806 ; v2(1326,856) 1326,825 1345,806 ; v2(1409,1075) 1409,1280.5 1557.5,1429 ; C8.2@1599.68,1585.69 1599.68,1557 1598.68,1556 1580,1556 1579,1555 1579,1497.1 ; U1.28@1603.01,1064.03 1571,1064.03 1570,1063.03 1510,1063.03 ; U1.50@1603.01,1497.1 1579,1497.1 ; C11.2@1617.32,955 1617.32,929.1 1613.22,925 1556.92,925 1552.82,929.1 1552.82,987.18 1510,1030 1510,1063.03 ; 1345,806 R14.1@1365.41,806 1365.41,878.08 1354.28,889.21 1354.28,911 1355.28,912 1403,912 1416,925 U1.19@1416,955.76 1416,987.5 1355,1048.5 1355,1084.9 ; 1355,1084.9 1355,1168.84 1376,1189.84 1376,1366 1443.1,1433.1 1553.4,1433.1 1557.5,1429 ; 1510,1063.03 1477.27,1063.03 1433,1107.3 1433,1214.99 1565.47,1347.46 1565.47,1491.34 1571.23,1497.1 ; 1557.5,1429 1557.5,1489.6 1565,1497.1 1571.23,1497.1 ; 1571.23,1497.1 1579,1497.1
  Bottom Layer w7: JP1.4@390,1040 351.58,1001.58 351.58,920 370,901.58 433.58,901.58 535,1003 535,1250 554,1269 646,1269 665,1250 665,905 J1.3@625,865 685.5,804.5 ; v2(813,202) 732.5,202 714,220.5 714,776 685.5,804.5 ; v2(830,805) 686,805 685.5,804.5 ; v2(920,867.5) 1084.5,867.5 1125,827 1297,827 v2(1326,856) ; R13.2@1095,1128.08 R12.2@1145,1128.08 ; P2.4@1158.66,1255.88 1158.66,1224 1166,1216.66 1166,1132 1165,1131 1145,1131 R12.2@1145,1128.08 ; v2(1409,1075) 1370,1036 1320.3,1036 1295,1061.3 R17.2@1295,1128.08 R18.2@1245,1128.08 R11.2@1195,1128.08 R12.2@1145,1128.08
VDDA: C7.1 C30.1 U1.22 | length 234.5
  Top Layer w7: U1.22@1475.06,955.76 1477.86,952.96 1477.86,930.71 1484.92,923.64 1532.58,923.64 1536.68,919.54 C7.1@1536.68,890 1536.68,887.32 1587,837 C30.1@1587,795.57
VREF+: C6.2 C27.1 R14.2 U1.21 | length 378.3
  Top Layer w7: C6.2@1445.48,890 1453.79,898.31 1453.79,903.19 1453.8,919.2 ; U1.21@1455.37,955.76 1453.8,954.19 1453.8,922 1453.8,919.2 ; C27.1@1496,795.57 1461.43,795.57 1451,806 R14.2@1416.59,806 1429.82,819.23 1429.82,824.82 1445.48,840.48 1502,840.48 1506.1,844.58 1506.1,900.45 1495.45,911.1 1461.9,911.1 1453.8,919.2
pads on no net: J2.A2 J2.A3 J2.A5 J2.A8 J2.A10 J2.A11 J2.B2 J2.B3 J2.B5 J2.B8 J2.B10 J2.B11 J2.M JP2.1 JP3.5 JP4.5 P1.6 P2. P2.9 U1.1 U1.2 U1.3 U1.4 U1.5 U1.7 U1.8 U1.9 U1.15 U1.16 U1.17 U1.18 U1.23 U1.38 U1.39 U1.40 U1.41 U1.42 U1.43 U1.44 U1.45 U1.46 U1.48 U1.55 U1.56 U1.57 U1.58 U1.63 U1.65 U1.66 U1.69 U1.77 U1.82 U1.83 U1.84 U1.85 U1.86 U1.87 U1.88 U1.89 U1.90 U1.91 U1.93 U1.95 U1.96 U1.97 U1.98 U7.4 U8.4 U.9 U.10 U.14 U.16
copper on no net:
  other v3: 91.3,1148.78 91.3,1621.22

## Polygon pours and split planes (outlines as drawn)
GND on Top Layer "GND_L01_P000" (solid, pour order 0): 0,0 1955,0 1955,2115 0,2115
GND on Bottom Layer "GND_L02_P001" (solid, pour order 1): 0,0 1955,0 1955,2115 0,2115

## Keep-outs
Keep-Out Layer:
  the board outline again, w10

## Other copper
Bottom Layer:
  region net B_COM: 930,300 970,300 970,235 930,235
  region net B-: 770,695 810,695 810,625 770,625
